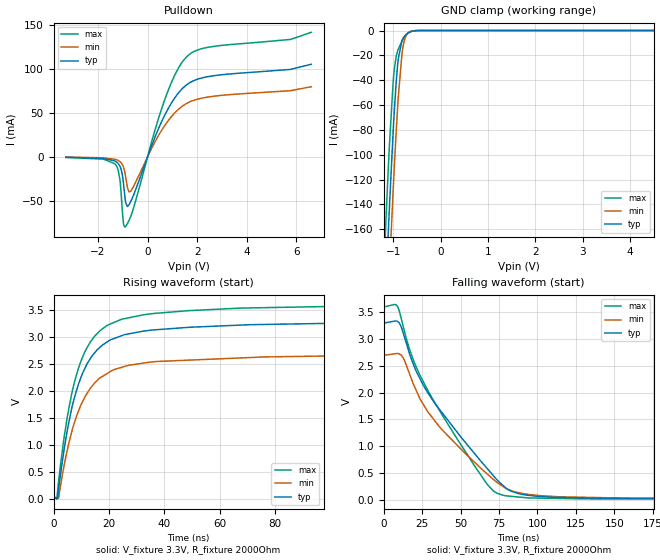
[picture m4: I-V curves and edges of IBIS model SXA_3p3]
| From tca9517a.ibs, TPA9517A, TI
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|   Model
[Model]   SXA_3p3
Model_type   I/O_open_drain
Polarity   Non-Inverting
Enable   Active-Low
Vinl = 0.99
Vinh = 2.31
Vmeas = 1.65
Vref = 3.3
Cref = 1pF
Rref = 2000
|   typ   min   max
C_comp   1.711pF   1.625pF   1.872pF
[Voltage Range]   3.3   2.7   3.6
[Temperature Range]   25   85   -40
[Pullup Reference]   3.3   2.7   3.6
[Pulldown Reference]   0   0   0
[Power Clamp Reference]   3.3   2.7   3.6
[GND Clamp Reference]   0   0   -0
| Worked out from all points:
|   slope of the pulldown table from 0 to 0.495 V, typ, clamps not added: 13.9 ohm
|   GND clamp passes 1 mA (typ) near -0.64 V on its own axis
|   falling waveform, V_fixture 3.3V, R_fixture 2000Ohm: 20-80 % time 46.9ns typ, 45.3ns min, 41ns max; typ from 3.3 V to 0.021 V
|   rising waveform, V_fixture 3.3V, R_fixture 2000Ohm: 20-80 % time 10.7ns typ, 11.6ns min, 10.3ns max; typ from 0.021 V to 3.3 V
[Pulldown]
|   Voltage   I(typ)   I(min)   I(max)
-3.3V     -650.4uA   -425.6uA   -872.6uA
-1.31V    -5.039mA   -3.037mA   -8.39mA
-1.122V   -10.6mA    -5.534mA   -25.33mA
-993.3mV  -25.91mA   -10.58mA   -71.14mA
-914.1mV  -46.47mA   -18.42mA   -80.3mA
-815.1mV  -56.84mA   -34.94mA   -76.28mA
-686.4mV  -51.44mA   -39.48mA   -68.41mA
600.6mV   42.09mA    31.66mA    57.71mA
1.125V    68.24mA    50.81mA    94.75mA
1.541V    81.2mA     60.15mA    112.9mA
2.373V    90.87mA    67.69mA    124.3mA
6.6V      105.3mA    79.74mA    141.7mA
[GND Clamp]
|   Voltage   I(typ)   I(min)   I(max)
-3.3V     -2.284A    -2.33A     -2.238A
-1.201V   -247.3mA   -299.4mA   -194.3mA
-1.152V   -203.6mA   -255.4mA   -151.2mA
-1.102V   -161.1mA   -212.3mA   -110.2mA
-1.082V   -144.7mA   -195.4mA   -94.65mA
-1.003V   -83.19mA   -130.6mA   -42.7mA
-983.4mV  -69.48mA   -115.3mA   -33.79mA
-894.3mV  -23.32mA   -54.46mA   -15.12mA
-815.1mV  -8.089mA   -18.97mA   -8.626mA
-785.4mV  -5.862mA   -11.6mA    -6.703mA
-636.9mV  -976.8uA   -981.4uA   -925.1uA
6.6V      0A         0A         0A
[POWER Clamp]
|   Voltage   I(typ)   I(min)   I(max)
-3.3V     0A         0A         0A
-3.28V    0A         0A         0A
-3.27V    0A         0A         0A
6.6V      0A         0A         0A
[Ramp]
R_load = 2000
|   typ   min   max
dV/dt_r   1.96764/1.07409e-08   1.60672/1.16044e-08   2.15/1.02532e-08
dV/dt_f   1.96746/4.69015e-08   1.60634/4.53508e-08   2.14995/4.09958e-08
[Falling Waveform]
V_fixture = 3.3V
V_fixture_min = 2.7V
V_fixture_max = 3.6V
R_fixture = 2000Ohm
C_fixture = 0F
|   Time   V(typ)   V(min)   V(max)
0s        3.3V       2.7V       3.6V
8.865ns   3.324V     2.726V     3.605V
12.66ns   3.106V     2.644V     3.231V
18.51ns   2.582V     2.216V     2.663V
29.64ns   1.955V     1.607V     1.988V
66.54ns   613.2mV    506.8mV    325.9mV
77.33ns   280.4mV    261.7mV    95.11mV
87.8ns    122.8mV    140.1mV    59.48mV
109ns     56.7mV     72.67mV    35.42mV
500ns     20.89mV    22.77mV    16.75mV
[Rising Waveform]
V_fixture = 3.3V
V_fixture_min = 2.7V
V_fixture_max = 3.6V
R_fixture = 2000Ohm
C_fixture = 0F
|   Time   V(typ)   V(min)   V(max)
0s        20.58mV    22.08mV    16.66mV
1.163ns   9.54mV     12.3mV     -13.21mV
1.452ns   975.5uV    9.865mV    132.4mV
3.814ns   907.4mV    608.7mV    1.135V
6.444ns   1.642V     1.212V     1.916V
11.53ns   2.438V     1.904V     2.746V
19.93ns   2.925V     2.338V     3.226V
32.57ns   3.108V     2.514V     3.41V
123.3ns   3.272V     2.663V     3.586V
500ns     3.3V       2.7V       3.6V
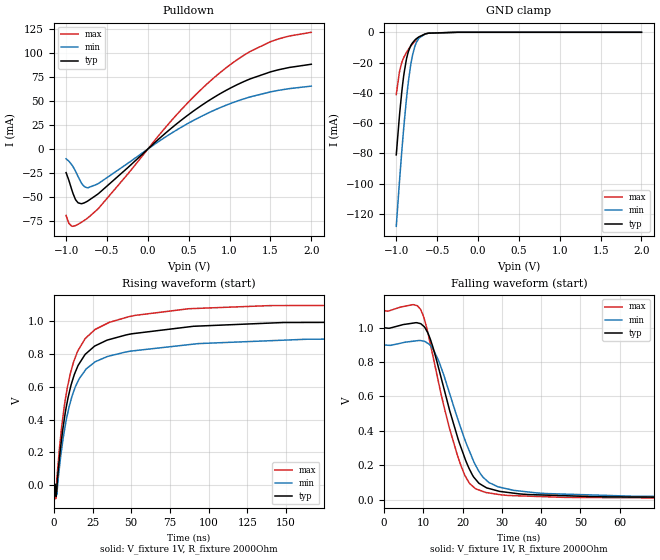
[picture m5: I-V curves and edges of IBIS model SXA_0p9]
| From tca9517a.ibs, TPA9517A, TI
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|   Model
[Model]   SXA_0p9
Model_type   I/O_open_drain
Polarity   Non-Inverting
Enable   Active-Low
Vinl = 0.3
Vinh = 0.7
Vmeas = 0.5
Vref = 1
Cref = 1pF
Rref = 2000
|   typ   min   max
C_comp   1.711pF   1.625pF   1.872pF
[Voltage Range]   1   0.9   1.1
[Temperature Range]   25   85   -40
[Pullup Reference]   1   0.9   1.1
[Pulldown Reference]   0   0   0
[Power Clamp Reference]   1   0.9   1.1
[GND Clamp Reference]   0   0   0
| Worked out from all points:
|   slope of the pulldown table from 0 to 0.15 V, typ, clamps not added: 12.9 ohm
|   GND clamp passes 1 mA (typ) near -0.64 V on its own axis
|   falling waveform, V_fixture 1V, R_fixture 2000Ohm: 20-80 % time 7.71ns typ, 8.37ns min, 7.17ns max; typ from 1 V to 0.006 V
|   rising waveform, V_fixture 1V, R_fixture 2000Ohm: 20-80 % time 16.7ns typ, 18ns min, 15.8ns max; typ from 0.006 V to 1 V
[Pulldown]
|   Voltage   I(typ)   I(min)   I(max)
-1V       -24.51mA   -10.15mA   -69.09mA
-967mV    -32.24mA   -12.55mA   -77.09mA
-931mV    -42.1mA    -16.22mA   -80.18mA
-880mV    -53.14mA   -23.81mA   -79.38mA
-853mV    -55.91mA   -28.66mA   -78.19mA
-775mV    -55.83mA   -39.09mA   -74.07mA
-598mV    -45.88mA   -35.45mA   -61.18mA
392mV     28.86mA    21.81mA    39.35mA
884mV     57.51mA    43.02mA    79.45mA
1.22V     71.81mA    53.38mA    99.84mA
1.505V    80.35mA    59.52mA    111.8mA
2V        88.17mA    65.43mA    121.4mA
[GND Clamp]
|   Voltage   I(typ)   I(min)   I(max)
-1V       -80.91mA   -128.1mA   -41.12mA
-964mV    -57.01mA   -100.8mA   -27.12mA
-922mV    -34.31mA   -71.61mA   -18.43mA
-877mV    -18.17mA   -44.83mA   -13.46mA
-850mV    -12.46mA   -31.8mA    -11.19mA
-826mV    -9.19mA    -22.48mA   -9.391mA
-802mV    -6.992mA   -15.34mA   -7.749mA
-763mV    -4.65mA    -7.87mA    -5.41mA
-721mV    -2.965mA   -3.81mA    -3.376mA
-607mV    -601.3uA   -604.4uA   -516.4uA
-250mV    -87.35nA   -352nA     0A
2V        0A         0A         0A
[POWER Clamp]
|   Voltage   I(typ)   I(min)   I(max)
-1V       0A         0A         0A
-994mV    0A         0A         0A
-991mV    0A         0A         0A
2V        0A         0A         0A
[Ramp]
R_load = 2000
|   typ   min   max
dV/dt_r   0.596261/1.65362e-08   0.535578/1.77292e-08   0.656946/1.56422e-08
dV/dt_f   0.596231/7.70954e-09   0.535499/8.36186e-09   0.656941/7.15986e-09
[Falling Waveform]
V_fixture = 1V
V_fixture_min = 0.9V
V_fixture_max = 1.1V
R_fixture = 2000Ohm
C_fixture = 0F
|   Time   V(typ)   V(min)   V(max)
0s        1V         900mV      1.1V
9.233ns   1.024V     925.5mV    1.109V
11.31ns   962.3mV    907mV      955.8mV
13.97ns   760.2mV    805.1mV    674.1mV
16.81ns   511.4mV    610.6mV    404.5mV
20.37ns   255.1mV    363.1mV    152.8mV
24.96ns   84.02mV    137.7mV    49.12mV
29.93ns   46.13mV    69.56mV    27.15mV
112.7ns   9.506mV    12.06mV    7.177mV
500ns     6.281mV    7.5mV      5.098mV
[Rising Waveform]
V_fixture = 1V
V_fixture_min = 0.9V
V_fixture_max = 1.1V
R_fixture = 2000Ohm
C_fixture = 0F
|   Time   V(typ)   V(min)   V(max)
0s        6.219mV    7.336mV    5.081mV
1.202ns   -17.29mV   304.6uV    -81.62mV
1.529ns   -68.21mV   -17.79mV   -27.78mV
1.936ns   -17.95mV   -54.9mV    32.08mV
7.089ns   423.3mV    346.8mV    502.4mV
15.27ns   720.9mV    627.3mV    814mV
26.55ns   848.8mV    750.9mV    948.5mV
48.02ns   918.3mV    814.4mV    1.026V
148.3ns   991.3mV    883.7mV    1.094V
500ns     1V         900mV      1.1V
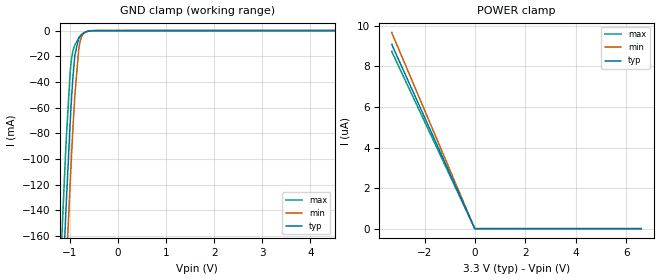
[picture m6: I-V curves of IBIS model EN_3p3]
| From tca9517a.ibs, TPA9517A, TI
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|   Model
[Model]   EN_3p3
Model_type   Input
Vinl = 0.99
Vinh = 2.31
|   typ   min   max
C_comp   0.975pF   0.923pF   1.047pF
[Voltage Range]   3.3   2.7   3.6
[Temperature Range]   25   85   -40
[Power Clamp Reference]   3.3   2.7   3.6
[GND Clamp Reference]   0   0   -0
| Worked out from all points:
|   GND clamp passes 1 mA (typ) near -0.66 V on its own axis
[GND Clamp]
|   Voltage   I(typ)   I(min)   I(max)
-3.3V     -2.284A    -2.33A     -2.238A
-1.191V   -236.7mA   -288.6mA   -183.9mA
-1.142V   -192.9mA   -244.5mA   -140.7mA
-1.092V   -150.5mA   -201.4mA   -99.66mA
-1.073V   -134mA     -184.5mA   -84.2mA
-983.4mV  -65.89mA   -112mA     -28.94mA
-933.9mV  -35.84mA   -75.73mA   -15.52mA
-894.3mV  -19.13mA   -50.23mA   -11.15mA
-805.2mV  -5.164mA   -12.47mA   -5.746mA
-755.7mV  -3.051mA   -4.779mA   -3.588mA
-676.5mV  -1.211mA   -1.241mA   -1.278mA
6.6V      0A         0A         0A
[POWER Clamp]
|   Voltage   I(typ)   I(min)   I(max)
-3.3V     9.102uA    9.682uA    8.75uA
-3.29V    9.054uA    9.63uA     8.705uA
-13.2mV   14.9nA     15.68nA    15.17nA
6.6V      0A         0A         0A
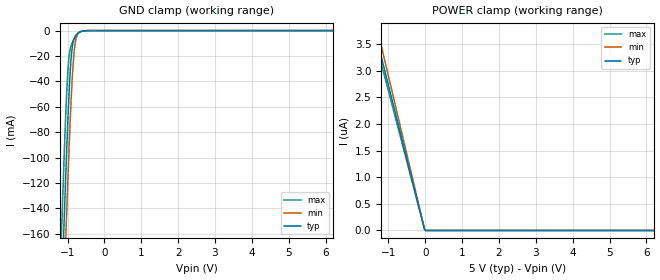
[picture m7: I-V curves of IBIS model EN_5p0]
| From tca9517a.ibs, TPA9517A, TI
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|   Model
[Model]   EN_5p0
Model_type   Input
Vinl = 1.5
Vinh = 3.5
|   typ   min   max
C_comp   0.975pF   0.923pF   1.047pF
[Voltage Range]   5   4.5   5.5
[Temperature Range]   25   85   -40
[Power Clamp Reference]   5   4.5   5.5
[GND Clamp Reference]   0   0   0
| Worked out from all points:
|   GND clamp passes 1 mA (typ) near -0.65 V on its own axis
[GND Clamp]
|   Voltage   I(typ)   I(min)   I(max)
-5V       -3.969A    -4.012A    -3.926A
-1.16V    -208.9mA   -260.6mA   -156.4mA
-1.115V   -169.7mA   -221.1mA   -118.1mA
-1.085V   -144.4mA   -195.2mA   -93.88mA
-1.04V    -107.8mA   -157.3mA   -60.65mA
-980mV    -63.58mA   -109.4mA   -27.58mA
-920mV    -29.11mA   -66.35mA   -13.64mA
-875mV    -13.8mA    -39.42mA   -9.732mA
-830mV    -6.983mA   -19.67mA   -7.025mA
-770mV    -3.547mA   -6.291mA   -4.163mA
-620mV    -531.2uA   -518.9uA   -477.9uA
10V       0A         0A         0A
[POWER Clamp]
|   Voltage   I(typ)   I(min)   I(max)
-5V       13.79uA    14.68uA    13.26uA
-1.895V   5.195uA    5.526uA    4.996uA
-1.25V    3.416uA    3.634uA    3.285uA
-20mV     23.37nA    24.82nA    23.73nA
10mV      0A         0A         0A
10V       0A         0A         0A
